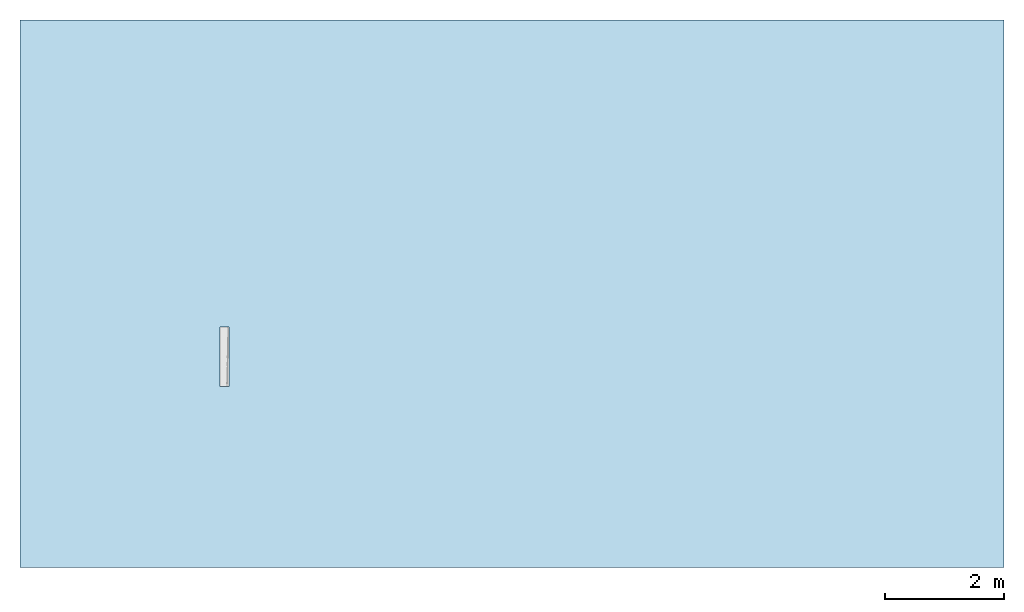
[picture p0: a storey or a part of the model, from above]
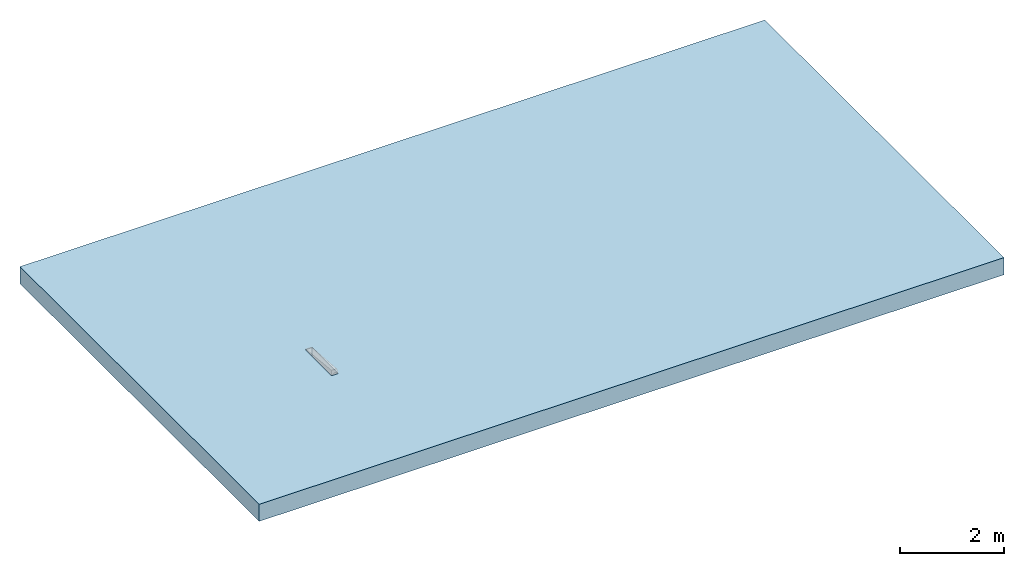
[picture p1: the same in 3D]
Properties of the parts of a building model (IFC2X3)

# File
Description: ViewDefinition [CoordinationView]
File name: 4234 - LH drop kerb - 1000mm LG.ifc
Time: 2013-09-02T12:41:20
Written by: Autodesk Revit 2013
Made in: 20120221_2030(x64)

# IfcProject, Project Number
LongName: Project Name; Phase: Project Status

# IfcSite, Default
RefLatitude: 42, 21, 30, 344238; RefLongitude: -71, -3, -35, -194702; RefElevation: 0 mm

# IfcBuilding
Pset_BuildingCommon - NumberOfStoreys: 1
Other - Project Issue Date: Issue Date; Project Status: Project Status; Project Name: Project Name; Client Name: Owner; Project Address: ## Street City, State Zip; Project Number: Project Number

# IfcBuildingStorey, Level 1
LongName: Level 1; Elevation: 0 mm
Constraints - Elevation Base: 0; Elevation: 0 mm
Graphics - Line Pattern: Center; Symbol at End 1 Default: no; Symbol: M_Level Head - Circle: M_Level Head - Circle; Color: 0; Symbol at End 2 Default: yes; Line Weight: 1
Identity Data - Structural: no; Building Story: yes; Name: Level 1
Dimensions - Computation Height: 0 mm

# IfcBuildingElementProxy: 4234 - LH drop kerb - 1000mm LG, Civil-Drainage-Channel-ACO-KerbDrain-HB405:4234 - LH drop kerb - 1000mm LG:4234 - LH drop kerb - 1000mm LG:312781
In: Level 1
Material: ACO Polymer Concrete.
Constraints - Level: Level: Level 1; Moves With Nearby Elements: no
Phasing - Phase Created: New Construction
Dimensions - Volume: 29812511 mm3; Void Length: 1000 mm; Circular Void Depth: 2000 mm; Void Width: 150 mm; Void Depth: -280 mm
Pset_BuildingElementProxyCommon - Reference: 4234 - LH drop kerb - 1000mm LG
Data - Load Class: A 15 - D 400; Product Standard: BS EN 1433:2002, CE marked, Kitemarked; Connection Pipe O.D: N/A; Channel C.S.A: 0.03 to 0.02mm²; Concrete Surround Volume - Load Class A 15 - D 400 - Grass or Asphalt Pavement: N/A; Product Weight: 62.1 Kg; Drainage Slot Intake area: N/A; Product Dimensions: 1000mm x 150mm x 405/305mm (LxWxH); Installation - Concrete Grade: Refer to brochure; Hydraulic Performance: http://www.aco.co.uk/download.php?id=120; Drainage Slot Width: N/A; Concrete Surround Volume - Load Class A 15 - D 400 - Concrete Pavement: N/A; ACO Hydraulic Design Software: http://www.acodesign.co.uk; Invert Depth: 380/280mm
General - SerialNumber: 0.000000; TagNumber: 0.000000
Identity Data - Telephone: +44 (0)1462 816666; OmniClass Title: Rainwater Removal; Address: ACO Business Park, Hitchin Road, Shefford, Bedfordshire, United Kingdom SG17 5TE ACO Business Park, Hitchin Road, Shefford, Bedfordshire, United Kingdom SG17 5TE ACO Business Park, Hitchin Road, Shefford, Bedfordshire, United Kingdom SG17 5TE; Maintenance guidelines: http://www.aco.co.uk/download.php?id=120; Installation guidelines: http://www.aco.co.uk/download.php?id=120; Product Code: 4234; Product Page URL: http://www.aco.co.uk/product_detail.php?id=3; URL: www.aco.co.uk; Fax: +44 (0)1462 815895; Product brochure: http://www.aco.co.uk/download.php?id=120; Model Description: Combined kerb and drainage system; Model: ACO KerbDrain HB405; OmniClass Number: 23.70.50.24; Price: POA - contact ACO; Type Comments: ACO KerbDrain HB405 half battered left-hand drop kerb unit 1000mm long; Manufacturer: ACO Technologies plc - ACO Water Management Division; e-mail Technical: technical@aco.co.uk; Assembly Description: Rain Water Drainage; Cost: 0; e-mail Sales: customersupport@aco.co.uk; Assembly Code: D2040
Materials and Finishes - Channel Material: Vienite® Synthetic Resin Concrete; Access Cover/Frame Finish: N/A; Access Cover/Frame Colour: N/A; Access Cover/Frame Material: N/A; Connection Pipe Material: N/A; Channel Colour: Grey; End Cap Material: N/A; End Cap Colour: N/A; Connection Pipe Material Colour: N/A
Green Building Properties - End Cap Recycled Material Content: N/A; Channel Recyclable: Fully recyclable; Access Cover/Frame Recycled Material Content: N/A; End Cap Recyclable: N/A; Access Cover/Frame Recyclable: N/A; Channel Recycled Material Content: 20% minimum
Construction - HB405 500_blindunit: no; Centre Stone: no; Access Unit: no; LH inlet/outlet end cap: no; Closing end cap: no; HB405 - 500: no; LH drop kerb: yes; RH drop kerb: no; RH inlet/outlet end cap: no; HB405 - 1000: no
Other - Revision: 1; CreatedBy: www.aco.co.uk

# IfcOpeningElement: Recess (2)
In: Level 1
Structural - Enable Analytical Model: no; Structural: no
Dimensions - Area: 151470000 mm2; Perimeter: 51360 mm; Thickness: 400 mm; Volume: 60546000000 mm3
Constraints - Room Bounding: yes; Related to Mass: no; Height Offset From Level: 0 mm; Level: Level: Level 1
Phasing - Phase Created: New Construction
Construction - Default Thickness: 400 mm; Function: 0
Analytical Properties - Absorptance: 0.1; Roughness: 1
Graphics - Coarse Scale Fill Color: 0
Materials and Finishes - Structural Material: Plant

# IfcSlab: Floor:Generic Floor - 400mm, Floor:Generic Floor - 400mm:193825
In: Level 1
PredefinedType: FLOOR; Material: Plant 400 mm
Structural - Enable Analytical Model: no; Structural: no
Dimensions - Area: 151470000 mm2; Perimeter: 51360 mm; Thickness: 400 mm; Volume: 60546000000 mm3
Constraints - Room Bounding: yes; Related to Mass: no; Height Offset From Level: 0 mm; Level: Level: Level 1
Phasing - Phase Created: New Construction
Pset_SlabCommon - Reference: Generic Floor - 400mm; IsExternal: no; LoadBearing: yes
Construction - Default Thickness: 400 mm; Function: 0
Analytical Properties - Absorptance: 0.1; Roughness: 1
Graphics - Coarse Scale Fill Color: 0
Materials and Finishes - Structural Material: Plant
